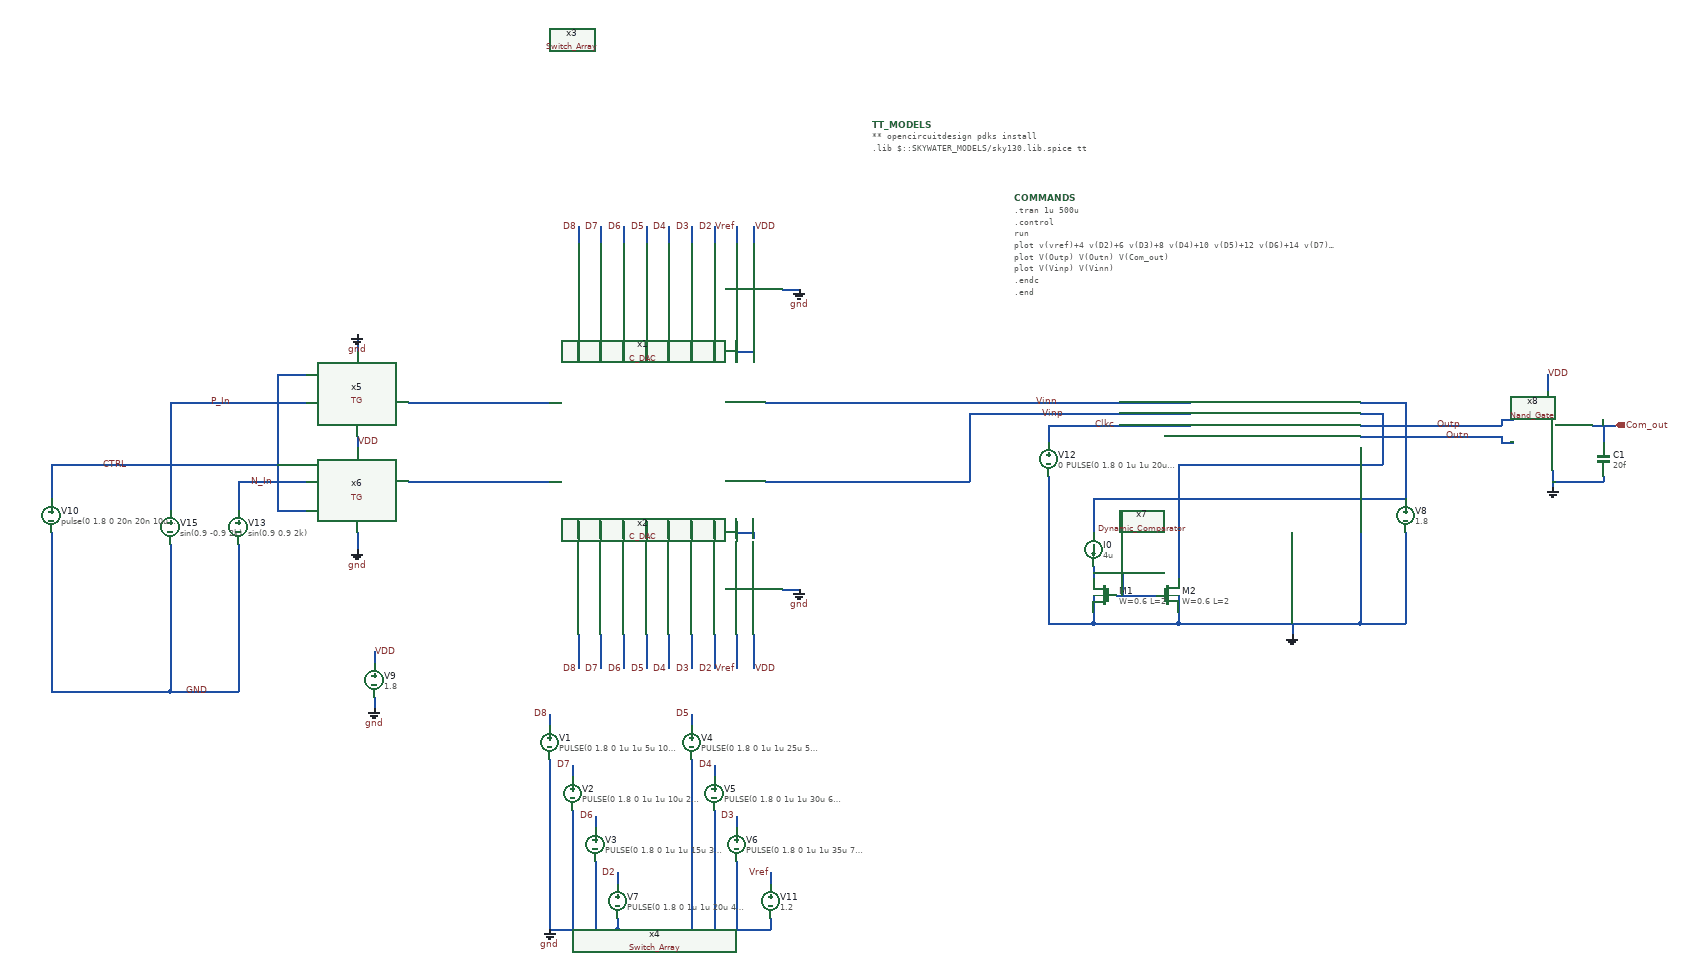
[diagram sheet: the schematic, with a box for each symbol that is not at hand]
v {xschem version=3.4.8RC file_version=1.2}
G {}
K {}
V {}
S {}
E {}
N -190 -500 -190 -460 {lab=#net1}
N -150 -500 -150 -460 {lab=#net2}
N -110 -500 -110 -460 {lab=#net3}
N -70 -500 -70 -460 {lab=#net4}
N -30 -500 -30 -460 {lab=#net5}
N 10 -500 10 -460 {lab=#net6}
N 50 -500 50 -460 {lab=#net7}
N 90 -500 90 -460 {lab=#net8}
N 120 -500 120 -480 {lab=#net8}
N 90 -480 120 -480 {lab=#net8}
N -190 -180 -190 -150 {lab=#net9}
N -150 -180 -150 -150 {lab=#net10}
N -110 -180 -110 -150 {lab=#net11}
N -70 -180 -70 -150 {lab=#net12}
N -30 -180 -30 -150 {lab=#net13}
N 10 -180 10 -150 {lab=#net14}
N 50 -180 50 -150 {lab=#net15}
N 90 -180 90 -150 {lab=#net16}
N 120 -160 120 -150 {lab=#net16}
N 90 -160 120 -160 {lab=#net16}
N -490 -390 -240 -390 {lab=#net17}
N -490 -250 -240 -250 {lab=#net18}
N -580 -330 -580 -310 {lab=VDD}
N -580 -160 -580 -130 {lab=gnd}
N -580 -510 -580 -480 {lab=gnd}
N -720 -440 -670 -440 {lab=CTRL}
N -720 -440 -720 -200 {lab=CTRL}
N -720 -200 -670 -200 {lab=CTRL}
N -790 -250 -670 -250 {lab=N_In}
N -790 -390 -670 -390 {lab=P_In}
N -190 20 -190 50 {lab=D8}
N -150 20 -150 50 {lab=D7}
N -110 20 -110 50 {lab=D6}
N -70 20 -70 50 {lab=D5}
N -30 20 -30 50 {lab=D4}
N 10 20 10 50 {lab=D3}
N 50 20 50 50 {lab=D2}
N 90 20 90 50 {lab=Vref}
N 120 20 120 50 {lab=VDD}
N 170 -60 200 -60 {lab=gnd}
N 170 -590 200 -590 {lab=gnd}
N 140 -390 340 -390 {lab=Vinn}
N 140 -250 340 -250 {lab=Vinp}
N -240 160 -240 180 {lab=D8}
N -240 240 -240 260 {lab=gnd}
N -200 250 -200 270 {lab=D7}
N -200 330 -200 350 {lab=gnd}
N -160 340 -160 360 {lab=D6}
N -160 420 -160 440 {lab=gnd}
N 10 160 10 180 {lab=D5}
N 10 240 10 260 {lab=gnd}
N 50 250 50 270 {lab=D4}
N 50 330 50 350 {lab=gnd}
N 90 340 90 360 {lab=D3}
N 90 420 90 440 {lab=gnd}
N -120 440 -120 460 {lab=D2}
N -120 520 -120 540 {lab=gnd}
N 150 440 150 460 {lab=Vref}
N 150 520 150 540 {lab=gnd}
N -550 50 -550 70 {lab=VDD}
N -550 130 -550 150 {lab=gnd}
N 1190 -330 1300 -330 {lab=Outn}
N 1190 -350 1300 -350 {lab=Outp}
N 1190 -310 1190 -260 {lab=GND}
N 1190 -260 1190 -160 {lab=GND}
N 870 -230 870 -80 {lab=#net19}
N 720 -20 720 0 {lab=GND}
N 720 0 870 0 {lab=GND}
N 870 -20 870 0 {lab=GND}
N 870 0 1190 0 {lab=GND}
N 1190 -160 1190 0 {lab=GND}
N 760 -50 830 -50 {lab=#net20}
N 720 -100 720 -80 {lab=#net20}
N 720 -50 720 -20 {lab=GND}
N 870 -50 870 -20 {lab=GND}
N 1270 -160 1270 0 {lab=GND}
N 1190 0 1270 0 {lab=GND}
N 1070 0 1070 20 {lab=GND}
N 640 -260 640 0 {lab=GND}
N 640 0 720 0 {lab=GND}
N -790 -140 -790 120 {lab=GND}
N -910 -140 -910 120 {lab=GND}
N -910 120 -790 120 {lab=GND}
N 640 -350 640 -320 {lab=Clkc}
N 640 -350 890 -350 {lab=Clkc}
N 500 -370 890 -370 {lab=Vinp}
N -790 -250 -790 -200 {lab=N_In}
N -910 -270 -910 -200 {lab=P_In}
N 380 -390 890 -390 {lab=Vinn}
N 1190 -390 1270 -390 {lab=#net21}
N 1270 -390 1270 -220 {lab=#net21}
N 720 -180 720 -160 {lab=#net21}
N 820 -220 1270 -220 {lab=#net21}
N 720 -220 820 -220 {lab=#net21}
N 720 -220 720 -180 {lab=#net21}
N 1190 -370 1230 -370 {lab=#net19}
N 1230 -370 1230 -280 {lab=#net19}
N 870 -280 1230 -280 {lab=#net19}
N 870 -280 870 -230 {lab=#net19}
N 340 -390 380 -390 {lab=Vinn}
N 340 -250 500 -250 {lab=Vinp}
N 500 -370 500 -250 {lab=Vinp}
N 720 -90 770 -90 {lab=#net20}
N 770 -90 770 -50 {lab=#net20}
N -910 -390 -910 -270 {lab=P_In}
N -910 -390 -790 -390 {lab=P_In}
N -190 50 -190 80 {lab=D8}
N -150 50 -150 80 {lab=D7}
N -110 50 -110 80 {lab=D6}
N -70 50 -70 80 {lab=D5}
N -30 50 -30 80 {lab=D4}
N 10 50 10 80 {lab=D3}
N 50 50 50 80 {lab=D2}
N 90 50 90 80 {lab=Vref}
N 120 50 120 80 {lab=VDD}
N -190 -700 -190 -670 {lab=D8}
N -150 -700 -150 -670 {lab=D7}
N -110 -700 -110 -670 {lab=D6}
N -70 -700 -70 -670 {lab=D5}
N -30 -700 -30 -670 {lab=D4}
N 10 -700 10 -670 {lab=D3}
N 50 -700 50 -670 {lab=D2}
N 90 -700 90 -670 {lab=Vref}
N 120 -700 120 -670 {lab=VDD}
N -240 260 -240 540 {lab=gnd}
N -240 540 -120 540 {lab=gnd}
N -160 440 -160 540 {lab=gnd}
N -200 350 -200 540 {lab=gnd}
N -120 540 150 540 {lab=gnd}
N 90 440 90 540 {lab=gnd}
N 50 350 50 540 {lab=gnd}
N 10 260 10 540 {lab=gnd}
N 1300 -350 1440 -350 {lab=Outp}
N 1440 -360 1440 -350 {lab=Outp}
N 1440 -360 1460 -360 {lab=Outp}
N 1300 -330 1440 -330 {lab=Outn}
N 1440 -330 1440 -320 {lab=Outn}
N 1440 -320 1460 -320 {lab=Outn}
N 1520 -440 1520 -410 {lab=VDD}
N 1600 -350 1640 -350 {lab=Com_out}
N 1530 -270 1530 -240 {lab=GND}
N 1620 -350 1620 -320 {lab=Com_out}
N 1620 -260 1620 -250 {lab=GND}
N 1530 -250 1620 -250 {lab=GND}
N -1120 -160 -1120 110 {lab=GND}
N -1120 110 -1120 120 {lab=GND}
N -1120 120 -910 120 {lab=GND}
N -1120 -280 -1120 -220 {lab=CTRL}
N -1120 -280 -720 -280 {lab=CTRL}
C {C_DAC.sym} -10 -430 2 1 {name=x1}
C {C_DAC.sym} -10 -210 0 0 {name=x2}
C {Switch_Array.sym} -200 -1030 0 0 {name=x3}
C {Switch_Array.sym} -200 380 2 1 {name=x4}
C {TG.sym} -670 -570 2 1 {name=x5}
C {TG.sym} -670 -70 0 0 {name=x6}
C {vsource.sym} -240 210 0 0 {name=V1 value="PULSE(0 1.8 0 1u 1u 5u 10u)" savecurrent=false}
C {vsource.sym} -200 300 0 0 {name=V2 value="PULSE(0 1.8 0 1u 1u 10u 20u)" savecurrent=false}
C {lab_wire.sym} -240 160 0 0 {name=p17 sig_type=std_logic lab=D8}
C {lab_wire.sym} -200 250 0 0 {name=p18 sig_type=std_logic lab=D7}
C {vsource.sym} -160 390 0 0 {name=V3 value="PULSE(0 1.8 0 1u 1u 15u 30u)" savecurrent=false}
C {vsource.sym} 10 210 0 0 {name=V4 value="PULSE(0 1.8 0 1u 1u 25u 50u)" savecurrent=false}
C {vsource.sym} 50 300 0 0 {name=V5 value="PULSE(0 1.8 0 1u 1u 30u 60u)" savecurrent=false}
C {lab_wire.sym} 50 250 0 0 {name=p23 sig_type=std_logic lab=D4}
C {vsource.sym} 90 390 0 0 {name=V6 value="PULSE(0 1.8 0 1u 1u 35u 70u)" savecurrent=false}
C {lab_wire.sym} 90 340 0 0 {name=p32 sig_type=std_logic lab=D3}
C {lab_wire.sym} -160 340 0 0 {name=p19 sig_type=std_logic lab=D6}
C {lab_wire.sym} 10 160 0 0 {name=p21 sig_type=std_logic lab=D5}
C {vsource.sym} -120 490 0 0 {name=V7 value="PULSE(0 1.8 0 1u 1u 20u 40u)" savecurrent=false}
C {vsource.sym} 150 490 0 0 {name=V11 value=1.2 savecurrent=false}
C {lab_wire.sym} -120 440 0 0 {name=p34 sig_type=std_logic lab=D2}
C {lab_wire.sym} 150 440 0 0 {name=p35 sig_type=std_logic lab=Vref}
C {vsource.sym} -550 100 0 0 {name=V9 value=1.8 savecurrent=false}
C {lab_wire.sym} -550 50 0 1 {name=p26 sig_type=std_logic lab=VDD}
C {vsource.sym} 1270 -190 0 0 {name=V8 value=1.8 savecurrent=false}
C {vsource.sym} 640 -290 0 0 {name=V12 value="0 PULSE(0 1.8 0 1u 1u 20u 40u)" savecurrent=false}
C {vsource.sym} -790 -170 0 0 {name=V13 value="sin(0.9 0.9 2k)" savecurrent=false}
C {vsource.sym} -910 -170 0 0 {name=V15 value="sin(0.9 -0.9 2k)" savecurrent=false}
C {sky130_fd_pr/nfet_01v8.sym} 850 -50 0 0 {name=M2
L=2
W=0.6
nf=1 mult=2
model=nfet_01v8
spiceprefix=X
}
C {sky130_fd_pr/nfet_01v8.sym} 740 -50 0 1 {name=M1
L=2
W=0.6 
nf=1 mult=2
model=nfet_01v8
spiceprefix=X
}
C {isource.sym} 720 -130 0 0 {name=I0 value=4u}
C {gnd.sym} 1070 20 0 0 {name=l2 lab=GND}
C {lab_wire.sym} 660 -390 0 0 {name=p4 sig_type=std_logic lab=Vinn}
C {lab_wire.sym} 670 -370 0 0 {name=p5 sig_type=std_logic lab=Vinp}
C {lab_wire.sym} 720 -350 2 0 {name=p6 sig_type=std_logic lab=Clkc}
C {Dynamic_Comparator.sym} 1040 -350 0 0 {name=x7}
C {lab_wire.sym} -840 120 3 0 {name=p7 sig_type=std_logic lab=GND}
C {lab_wire.sym} -190 80 0 0 {name=p10 sig_type=std_logic lab=D8}
C {lab_wire.sym} -150 80 0 0 {name=p11 sig_type=std_logic lab=D7}
C {lab_wire.sym} -110 80 0 0 {name=p12 sig_type=std_logic lab=D6}
C {lab_wire.sym} -70 80 0 0 {name=p15 sig_type=std_logic lab=D5}
C {lab_wire.sym} -30 80 0 0 {name=p16 sig_type=std_logic lab=D4}
C {lab_wire.sym} 10 80 0 0 {name=p24 sig_type=std_logic lab=D3}
C {lab_wire.sym} 50 80 0 0 {name=p30 sig_type=std_logic lab=D2}
C {lab_wire.sym} 90 80 0 0 {name=p38 sig_type=std_logic lab=Vref}
C {lab_wire.sym} 120 80 0 1 {name=p39 sig_type=std_logic lab=VDD}
C {lab_wire.sym} -190 -700 2 1 {name=p40 sig_type=std_logic lab=D8}
C {lab_wire.sym} -150 -700 2 1 {name=p41 sig_type=std_logic lab=D7}
C {lab_wire.sym} -110 -700 2 1 {name=p42 sig_type=std_logic lab=D6}
C {lab_wire.sym} -70 -700 2 1 {name=p43 sig_type=std_logic lab=D5}
C {lab_wire.sym} -30 -700 2 1 {name=p44 sig_type=std_logic lab=D4}
C {lab_wire.sym} 10 -700 2 1 {name=p45 sig_type=std_logic lab=D3}
C {lab_wire.sym} 50 -700 2 1 {name=p46 sig_type=std_logic lab=D2}
C {lab_wire.sym} 90 -700 2 1 {name=p47 sig_type=std_logic lab=Vref}
C {lab_wire.sym} 120 -700 2 0 {name=p48 sig_type=std_logic lab=VDD}
C {devices/code.sym} 330 -880 0 0 {name=TT_MODELS
only_toplevel=true
format="tcleval( @value )"
value="
** opencircuitdesign pdks install
.lib $::SKYWATER_MODELS/sky130.lib.spice tt
"
spice_ignore=false}
C {simulator_commands_shown.sym} 580 -750 0 0 {name=COMMANDS
simulator=ngspice
only_toplevel=false 
value="
.tran 1u 500u
.control
run
plot v(vref)+4 v(D2)+6 v(D3)+8 v(D4)+10 v(D5)+12 v(D6)+14 v(D7)+16 v(D8)+18
plot V(Outp) V(Outn) V(Com_out)
plot V(Vinp) V(Vinn)
.endc
.end
"}
C {lab_wire.sym} -580 -320 0 1 {name=p14 sig_type=std_logic lab=VDD}
C {gnd.sym} -550 150 0 0 {name=l1 lab=gnd}
C {gnd.sym} -580 -130 0 0 {name=l3 lab=gnd}
C {gnd.sym} -580 -510 2 0 {name=l5 lab=gnd}
C {gnd.sym} 200 -60 0 0 {name=l4 lab=gnd}
C {gnd.sym} 200 -590 0 0 {name=l6 lab=gnd}
C {gnd.sym} -240 540 0 0 {name=l7 lab=gnd}
C {Nand_Gate.sym} 1580 -190 0 0 {name=x8}
C {lab_wire.sym} 1340 -330 2 0 {name=p2 sig_type=std_logic lab=Outn}
C {lab_wire.sym} 1370 -350 0 0 {name=p3 sig_type=std_logic lab=Outp}
C {gnd.sym} 1530 -240 0 0 {name=l8 lab=GND}
C {lab_wire.sym} 1520 -440 0 1 {name=p1 sig_type=std_logic lab=VDD}
C {opin.sym} 1640 -350 0 0 {name=p8 lab=Com_out}
C {capa.sym} 1620 -290 0 0 {name=C1
m=1
value=20f
footprint=1206
device="ceramic capacitor"}
C {vsource.sym} -1120 -190 0 0 {name=V10 value="pulse(0 1.8 0 20n 20n 10u 40u)" savecurrent=false}
C {lab_wire.sym} -1030 -280 0 1 {name=p9 sig_type=std_logic lab=CTRL}
C {lab_wire.sym} -840 -390 0 1 {name=p13 sig_type=std_logic lab=P_In}
C {lab_wire.sym} -770 -250 0 1 {name=p20 sig_type=std_logic lab=N_In}
